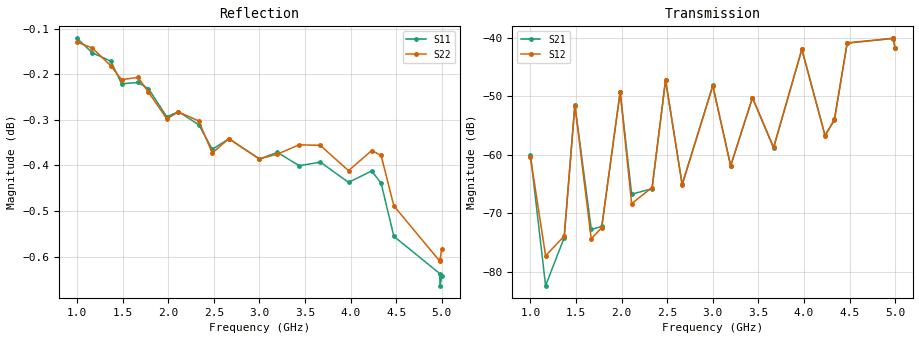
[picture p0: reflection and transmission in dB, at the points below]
!Keysight Technologies,N5242A,MY48420869,A.10.65.01
!Date: Wednesday, September 11, 2019 19:24:35
!Correction: S33(Full 4 Port(1,2,3,4))
!S43(Full 4 Port(1,2,3,4))
!S34(Full 4 Port(1,2,3,4))
!S44(Full 4 Port(1,2,3,4))
!S2P File: Measurements: S33, S43, S34, S44:
!Created with skrf (http://scikit-rf.org).
# Hz S RI R 50.0
!freq ReS11 ImS11 ReS21 ImS21 ReS12 ImS12 ReS22 ImS22
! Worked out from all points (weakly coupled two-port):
!   4001 points, 1 GHz to 5 GHz, reference 50 ohm
!   highest |S21| = -40.10 dB at 4.977 GHz (marker M1); lowest = -82.4 dB at 1.166 GHz (marker M2)
!   lowest |S11| = -0.7 dB at 4.98 GHz (marker M3), VSWR 26.19, Z = 1.96 - j8.26 ohm
!   |S11| at or under -10 dB: nowhere
!   |S22| runs from -0.6 to -0.1 dB; largest |S21 - S12| = 0.00024
!   S11 on the Smith chart (normalised r, x): 1 GHz: 0.01, -0.68; 1.782 GHz: 0.01, +0.09; 2.664 GHz: 0.04, +1.08; 3.435 GHz: 4, +12; 4.231 GHz: 0.06, -1.25; 5 GHz: 0.04, -0.15
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1e9  -0.3601 -0.918  0.00099 0.000147  0.000935 0.000175  -0.3061 -0.9364
1.166e9  -0.6144 -0.7667  6.66e-05 -3.67e-05  0.000117 -7.14e-05  -0.572 -0.8003
1.37e9  -0.8449 -0.4974  9.35e-05 -0.000172  0.000107 -0.000171  -0.8188 -0.5372
1.487e9  -0.9228 -0.3143  -0.00251 -0.000929  -0.00246 -0.000938  -0.9088 -0.3556
1.667e9  -0.975 -0.0191  -2.19e-05 0.000229  -6.97e-06 0.000191  -0.9749 -0.0547
1.782e9  -0.9586 0.1706  4.34e-05 0.00024  2.94e-05 0.000237  -0.9624 0.1421
1.984e9  -0.8419 0.4752  0.00308 -0.00159  0.00306 -0.00154  -0.8493 0.4608
2.11e9  -0.7255 0.6409  -0.00027 -0.000373  -0.000224 -0.00031  -0.7292 0.6366
2.334e9  -0.4405 0.8584  -0.000478 -0.000188  -0.000484 -0.000204  -0.4303 0.8646
2.482e9  -0.217 0.934  -0.00077 0.00428  -0.00079 0.0043  -0.1959 0.9377
2.664e9  0.0749 0.9585  0.000559 -4.65e-05  0.00055 -2.2e-05  0.1097 0.9552
3e9  0.5775 0.7625  -0.0039 -0.000387  -0.00385 -0.00042  0.6153 0.7324
3.196e9  0.804 0.5212  -0.000444 0.000671  -0.000455 0.000664  0.8322 0.474
3.435e9  0.9447 0.1392  0.00108 0.00287  0.00106 0.0029  0.9563 0.0839
3.667e9  0.9194 -0.2612  -0.000262 -0.00111  -0.000273 -0.00113  0.9091 -0.3079
3.977e9  0.6193 -0.7216  -0.00513 0.00609  -0.00514 0.0061  0.5952 -0.7452
4.231e9  0.2075 -0.9308  0.00145 0.00027  0.00143 0.000254  0.1947 -0.9386
4.334e9  0.0144 -0.9506  0.00194 -0.000318  0.00198 -0.000313  0.0132 -0.9573
4.474e9  -0.2401 -0.9068  -0.00148 -0.00887  -0.00149 -0.00894  -0.2311 -0.9166
4.977e9  -0.8787 -0.3024  0.00931 0.00334  0.00929 0.00337  -0.8616 -0.3559
4.98e9  -0.8771 -0.2983  0.0095 0.00242  0.00959 0.00241  -0.8636 -0.3519
5e9  -0.889 -0.2683  0.00769 -0.00256  0.00772 -0.00259  -0.8774 -0.3235
